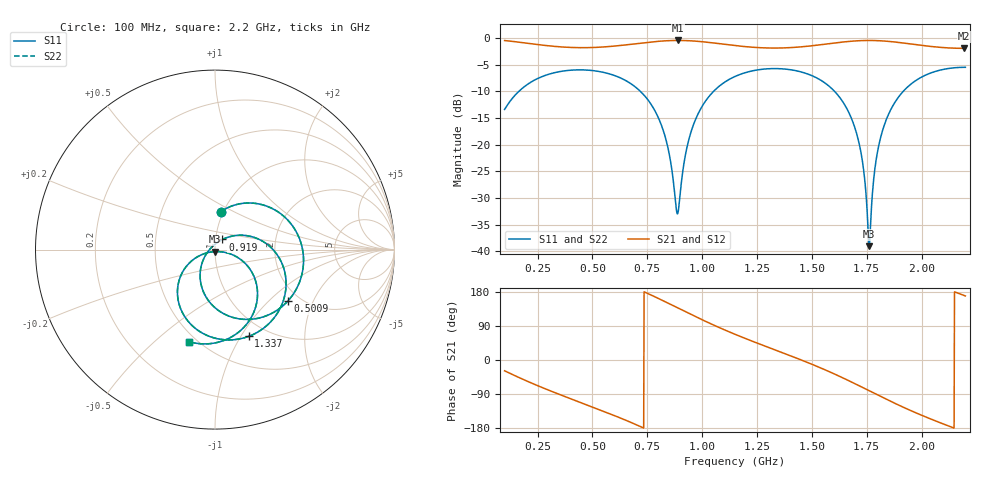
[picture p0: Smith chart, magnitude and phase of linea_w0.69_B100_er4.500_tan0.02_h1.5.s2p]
! Chirptenna · simulación 3D de una microstrip de dos puertos (S12 = S21, S22 = S11 por simetría)
# HZ S RI R 50
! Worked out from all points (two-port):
!   1101 points, 100 MHz to 2.2 GHz, reference 50 ohm
!   highest |S21| = -0.43 dB at 890.4 MHz (marker M1); lowest = -1.9 dB at 2.192 GHz (marker M2)
!   |S21| within 3 dB of the highest: start of sweep to end of sweep
!   lowest |S11| = -39.0 dB at 1.761 GHz (marker M3), VSWR 1.02, Z = 49.9 - j1.12 ohm
!   |S11| at or under -10 dB: start of sweep to 164.3 MHz; 719.4 MHz to 1.052 GHz (332.4 MHz wide, 37.5 % of centre); 1.604 GHz to 1.916 GHz (311.8 MHz wide, 17.7 % of centre)
!   |S22| runs from -39.0 to -5.5 dB; largest |S21 - S12| = 0
!   S11 on the Smith chart (normalised r, x): 100 MHz: 0.97, +0.43; 500.9 MHz: 1.73, -1.32; 919 MHz: 1.08, +0.12; 1.337 GHz: 0.82, -1.08; 2.2 GHz: 0.45, -0.65
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1e8  0.0337 0.212  0.8344 -0.4535  0.8344 -0.4535  0.0337 0.212
2.584545e8  0.3826 0.1864  0.3019 -0.8126  0.3019 -0.8126  0.3826 0.1864
4.512727e8  0.4636 -0.1986  -0.3218 -0.748  -0.3218 -0.748  0.4636 -0.1986
5.009091e8  0.4064 -0.2859  -0.4592 -0.6759  -0.4592 -0.6759  0.4064 -0.2859
6.498182e8  0.1223 -0.3836  -0.8029 -0.3184  -0.8029 -0.3184  0.1223 -0.3836
8.006364e8  -0.0826 -0.1594  -0.8908 0.2813  -0.8908 0.2813  -0.0826 -0.1594
8.445455e8  -0.0682 -0.0639  -0.8215 0.4708  -0.8215 0.4708  -0.0682 -0.0639
8.903636e8  -0.0112 0.0203  -0.6975 0.6473  -0.6975 0.6473  -0.0112 0.0203
9.19e8  0.0417 0.0566  -0.5973 0.7384  -0.5973 0.7384  0.0417 0.0566
9.991818e8  0.2172 0.0683  -0.2631 0.8884  -0.2631 0.8884  0.2172 0.0683
1.15e9  0.396 -0.1854  0.3213 0.7892  0.3213 0.7892  0.396 -0.1854
1.337091e9  0.1876 -0.4834  0.7282 0.3494  0.7282 0.3494  0.1876 -0.4834
1.501273e9  -0.1237 -0.4269  0.8319 -0.1683  0.8319 -0.1683  -0.1237 -0.4269
1.612e9  -0.2087 -0.2209  0.7014 -0.5724  0.7014 -0.5724  -0.2087 -0.2209
1.686455e9  -0.1457 -0.0776  0.4746 -0.8095  0.4746 -0.8095  -0.1457 -0.0776
1.728455e9  -0.0703 -0.0266  0.2997 -0.9003  0.2997 -0.9003  -0.0703 -0.0266
1.760909e9  -0.000891 -0.0112  0.1496 -0.9397  0.1496 -0.9397  -0.000891 -0.0112
1.797182e9  0.078 -0.0214  -0.0235 -0.9479  -0.0235 -0.9479  0.078 -0.0214
1.850636e9  0.1757 -0.0848  -0.2665 -0.8935  -0.2665 -0.8935  0.1757 -0.0848
2.005273e9  0.1938 -0.3914  -0.7151 -0.4653  -0.7151 -0.4653  0.1938 -0.3914
2.192364e9  -0.1326 -0.5163  -0.7922 0.1299  -0.7922 0.1299  -0.1326 -0.5163
2.2e9  -0.1469 -0.5124  -0.7882 0.153  -0.7882 0.153  -0.1469 -0.5124
